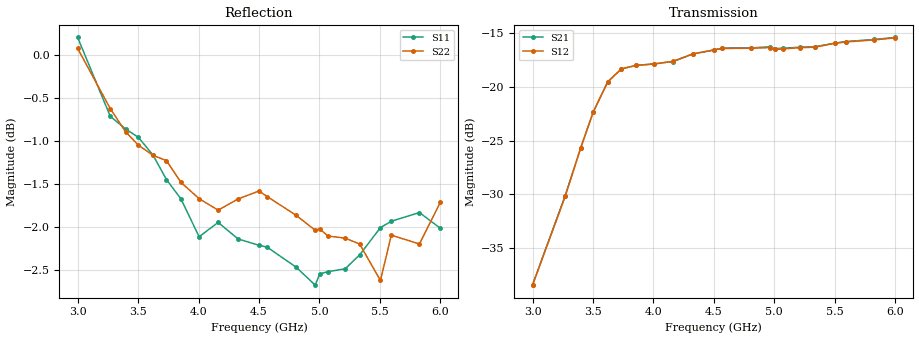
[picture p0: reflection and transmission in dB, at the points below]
!  26/11/2025  14:08:48
! Ref Plane: 0.000 mm
# MHZ S MA R  50
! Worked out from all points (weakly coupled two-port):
!   401 points, 3 GHz to 6 GHz, reference 50 ohm
!   highest |S21| = -15.37 dB at 6 GHz (marker M1); lowest = -38.5 dB at 3 GHz (marker M2)
!   lowest |S11| = -2.7 dB at 4.965 GHz (marker M3), VSWR 6.53, Z = 16.8 - j53.2 ohm
!   |S11| at or under -10 dB: nowhere
!   |S22| runs from -2.6 to 0.2 dB; largest |S21 - S12| = 0.0071
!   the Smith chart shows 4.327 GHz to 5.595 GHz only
!   S11 on the Smith chart (normalised r, x): 4.327 GHz: 0.17, +0.59; 4.567 GHz: 0.91, +2.33; 4.808 GHz: 1.30, -2.58; 5.07 GHz: 0.20, -0.62; 5.332 GHz: 0.13, +0.09; 5.595 GHz: 0.20, +0.87
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3000  1.024 -139.0  0.01193 53.1  0.0119 55.0  1.009 -105.2
3270  0.9211 151.2  0.03111 -16.3  0.03085 -14.2  0.9307 -171.1
3397.5  0.9056 108.0  0.05171 -57.8  0.05184 -56.5  0.9021 149.8
3502.5  0.8955 65.2  0.07658 -99.0  0.07653 -97.6  0.8862 111.9
3622.5  0.8747 14.4  0.1058 -151.3  0.1058 -149.9  0.8743 60.4
3735  0.8462 -34.7  0.1214 159.1  0.1215 160.7  0.868 11.3
3855  0.8245 -82.8  0.126 110.8  0.1261 112.5  0.843 -37.2
4005  0.7837 -137.0  0.1282 58.1  0.128 59.4  0.8248 -89.5
4162.5  0.799 169.8  0.1315 6.8  0.1318 8.5  0.8122 -139.3
4327.5  0.7814 117.5  0.1427 -45.3  0.1428 -43.5  0.8245 170.6
4500  0.7748 62.5  0.1487 -99.2  0.1489 -97.7  0.8333 117.5
4567.5  0.7729 41.5  0.1518 -120.0  0.1513 -118.6  0.8272 97.5
4807.5  0.7524 -35.1  0.1522 165.0  0.1516 166.7  0.8066 22.6
4965  0.7345 -83.4  0.1541 119.2  0.1528 120.8  0.7906 -20.7
5002.5  0.7456 -95.3  0.151 108.7  0.1497 110.0  0.792 -32.5
5070  0.7479 -114.7  0.1517 89.7  0.1505 90.9  0.7846 -52.0
5212.5  0.7507 -156.7  0.1533 49.6  0.1526 50.8  0.7822 -90.8
5332.5  0.7648 169.3  0.154 16.1  0.1533 17.5  0.7762 -126.7
5505  0.7934 118.9  0.1603 -32.9  0.1601 -30.8  0.7391 -176.0
5595  0.8002 96.7  0.163 -57.3  0.1623 -55.0  0.7854 159.2
5827.5  0.8096 26.4  0.1666 -125.4  0.1659 -123.2  0.7762 94.4
6000  0.7928 -20.6  0.1704 -172.9  0.1695 -171.2  0.8206 51.9
